# Abstract 64x7 single-port SRAM (pin interface of OpenROAD-flow-scripts' bsg_fakeram).
# Geometry is an assumption for a 16A-class node, not PDK data.
VERSION 5.8 ;
BUSBITCHARS "[]" ;
DIVIDERCHAR "/" ;

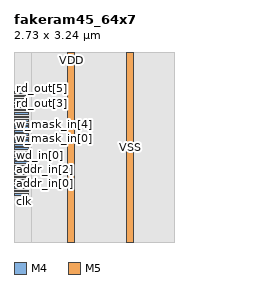
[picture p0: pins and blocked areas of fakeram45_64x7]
MACRO fakeram45_64x7
  CLASS BLOCK ;
  FOREIGN fakeram45_64x7 0 0 ;
  ORIGIN 0 0 ;
  SIZE 2.7300 BY 3.2400 ;
  SYMMETRY X Y R90 ;
  PIN clk
    DIRECTION INPUT ;
    USE CLOCK ;
    PORT
      LAYER M4 ;
        RECT 0 0.7950 0.2400 0.8250 ;
    END
  END clk
  PIN ce_in
    DIRECTION INPUT ;
    USE SIGNAL ;
    PORT
      LAYER M4 ;
        RECT 0 0.8550 0.2400 0.8850 ;
    END
  END ce_in
  PIN we_in
    DIRECTION INPUT ;
    USE SIGNAL ;
    PORT
      LAYER M4 ;
        RECT 0 0.9150 0.2400 0.9450 ;
    END
  END we_in
  PIN addr_in[0]
    DIRECTION INPUT ;
    USE SIGNAL ;
    PORT
      LAYER M4 ;
        RECT 0 0.9750 0.2400 1.0050 ;
    END
  END addr_in[0]
  PIN addr_in[1]
    DIRECTION INPUT ;
    USE SIGNAL ;
    PORT
      LAYER M4 ;
        RECT 0 1.0350 0.2400 1.0650 ;
    END
  END addr_in[1]
  PIN addr_in[2]
    DIRECTION INPUT ;
    USE SIGNAL ;
    PORT
      LAYER M4 ;
        RECT 0 1.0950 0.2400 1.1250 ;
    END
  END addr_in[2]
  PIN addr_in[3]
    DIRECTION INPUT ;
    USE SIGNAL ;
    PORT
      LAYER M4 ;
        RECT 0 1.1550 0.2400 1.1850 ;
    END
  END addr_in[3]
  PIN addr_in[4]
    DIRECTION INPUT ;
    USE SIGNAL ;
    PORT
      LAYER M4 ;
        RECT 0 1.2150 0.2400 1.2450 ;
    END
  END addr_in[4]
  PIN addr_in[5]
    DIRECTION INPUT ;
    USE SIGNAL ;
    PORT
      LAYER M4 ;
        RECT 0 1.2750 0.2400 1.3050 ;
    END
  END addr_in[5]
  PIN wd_in[0]
    DIRECTION INPUT ;
    USE SIGNAL ;
    PORT
      LAYER M4 ;
        RECT 0 1.3350 0.2400 1.3650 ;
    END
  END wd_in[0]
  PIN wd_in[1]
    DIRECTION INPUT ;
    USE SIGNAL ;
    PORT
      LAYER M4 ;
        RECT 0 1.3950 0.2400 1.4250 ;
    END
  END wd_in[1]
  PIN wd_in[2]
    DIRECTION INPUT ;
    USE SIGNAL ;
    PORT
      LAYER M4 ;
        RECT 0 1.4550 0.2400 1.4850 ;
    END
  END wd_in[2]
  PIN wd_in[3]
    DIRECTION INPUT ;
    USE SIGNAL ;
    PORT
      LAYER M4 ;
        RECT 0 1.5150 0.2400 1.5450 ;
    END
  END wd_in[3]
  PIN wd_in[4]
    DIRECTION INPUT ;
    USE SIGNAL ;
    PORT
      LAYER M4 ;
        RECT 0 1.5750 0.2400 1.6050 ;
    END
  END wd_in[4]
  PIN wd_in[5]
    DIRECTION INPUT ;
    USE SIGNAL ;
    PORT
      LAYER M4 ;
        RECT 0 1.6350 0.2400 1.6650 ;
    END
  END wd_in[5]
  PIN wd_in[6]
    DIRECTION INPUT ;
    USE SIGNAL ;
    PORT
      LAYER M4 ;
        RECT 0 1.6950 0.2400 1.7250 ;
    END
  END wd_in[6]
  PIN w_mask_in[0]
    DIRECTION INPUT ;
    USE SIGNAL ;
    PORT
      LAYER M4 ;
        RECT 0 1.7550 0.2400 1.7850 ;
    END
  END w_mask_in[0]
  PIN w_mask_in[1]
    DIRECTION INPUT ;
    USE SIGNAL ;
    PORT
      LAYER M4 ;
        RECT 0 1.8150 0.2400 1.8450 ;
    END
  END w_mask_in[1]
  PIN w_mask_in[2]
    DIRECTION INPUT ;
    USE SIGNAL ;
    PORT
      LAYER M4 ;
        RECT 0 1.8750 0.2400 1.9050 ;
    END
  END w_mask_in[2]
  PIN w_mask_in[3]
    DIRECTION INPUT ;
    USE SIGNAL ;
    PORT
      LAYER M4 ;
        RECT 0 1.9350 0.2400 1.9650 ;
    END
  END w_mask_in[3]
  PIN w_mask_in[4]
    DIRECTION INPUT ;
    USE SIGNAL ;
    PORT
      LAYER M4 ;
        RECT 0 1.9950 0.2400 2.0250 ;
    END
  END w_mask_in[4]
  PIN w_mask_in[5]
    DIRECTION INPUT ;
    USE SIGNAL ;
    PORT
      LAYER M4 ;
        RECT 0 2.0550 0.2400 2.0850 ;
    END
  END w_mask_in[5]
  PIN w_mask_in[6]
    DIRECTION INPUT ;
    USE SIGNAL ;
    PORT
      LAYER M4 ;
        RECT 0 2.1150 0.2400 2.1450 ;
    END
  END w_mask_in[6]
  PIN rd_out[0]
    DIRECTION OUTPUT ;
    USE SIGNAL ;
    PORT
      LAYER M4 ;
        RECT 0 2.1750 0.2400 2.2050 ;
    END
  END rd_out[0]
  PIN rd_out[1]
    DIRECTION OUTPUT ;
    USE SIGNAL ;
    PORT
      LAYER M4 ;
        RECT 0 2.2350 0.2400 2.2650 ;
    END
  END rd_out[1]
  PIN rd_out[2]
    DIRECTION OUTPUT ;
    USE SIGNAL ;
    PORT
      LAYER M4 ;
        RECT 0 2.2950 0.2400 2.3250 ;
    END
  END rd_out[2]
  PIN rd_out[3]
    DIRECTION OUTPUT ;
    USE SIGNAL ;
    PORT
      LAYER M4 ;
        RECT 0 2.3550 0.2400 2.3850 ;
    END
  END rd_out[3]
  PIN rd_out[4]
    DIRECTION OUTPUT ;
    USE SIGNAL ;
    PORT
      LAYER M4 ;
        RECT 0 2.4150 0.2400 2.4450 ;
    END
  END rd_out[4]
  PIN rd_out[5]
    DIRECTION OUTPUT ;
    USE SIGNAL ;
    PORT
      LAYER M4 ;
        RECT 0 2.4750 0.2400 2.5050 ;
    END
  END rd_out[5]
  PIN rd_out[6]
    DIRECTION OUTPUT ;
    USE SIGNAL ;
    PORT
      LAYER M4 ;
        RECT 0 2.5350 0.2400 2.5650 ;
    END
  END rd_out[6]
  PIN VDD
    DIRECTION INOUT ;
    USE POWER ;
    PORT
      LAYER M5 ;
        RECT 0.9200 0 1.0400 3.2400 ;
    END
  END VDD
  PIN VSS
    DIRECTION INOUT ;
    USE GROUND ;
    PORT
      LAYER M5 ;
        RECT 1.9200 0 2.0400 3.2400 ;
    END
  END VSS
  OBS
    LAYER BPR ;
      RECT 0 0 2.7300 3.2400 ;
    LAYER M0 ;
      RECT 0 0 2.7300 3.2400 ;
    LAYER M1 ;
      RECT 0 0 2.7300 3.2400 ;
    LAYER M2 ;
      RECT 0 0 2.7300 3.2400 ;
    LAYER M3 ;
      RECT 0 0 2.7300 3.2400 ;
    LAYER BPR2TOP ;
      RECT 0 0 2.7300 3.2400 ;
    LAYER VIA0 ;
      RECT 0 0 2.7300 3.2400 ;
    LAYER VIA1 ;
      RECT 0 0 2.7300 3.2400 ;
    LAYER VIA2 ;
      RECT 0 0 2.7300 3.2400 ;
    LAYER VIA3 ;
      RECT 0 0 2.7300 3.2400 ;
    LAYER M4 ;
      RECT 0.3000 0 2.7300 3.2400 ;
  END
END fakeram45_64x7

END LIBRARY
